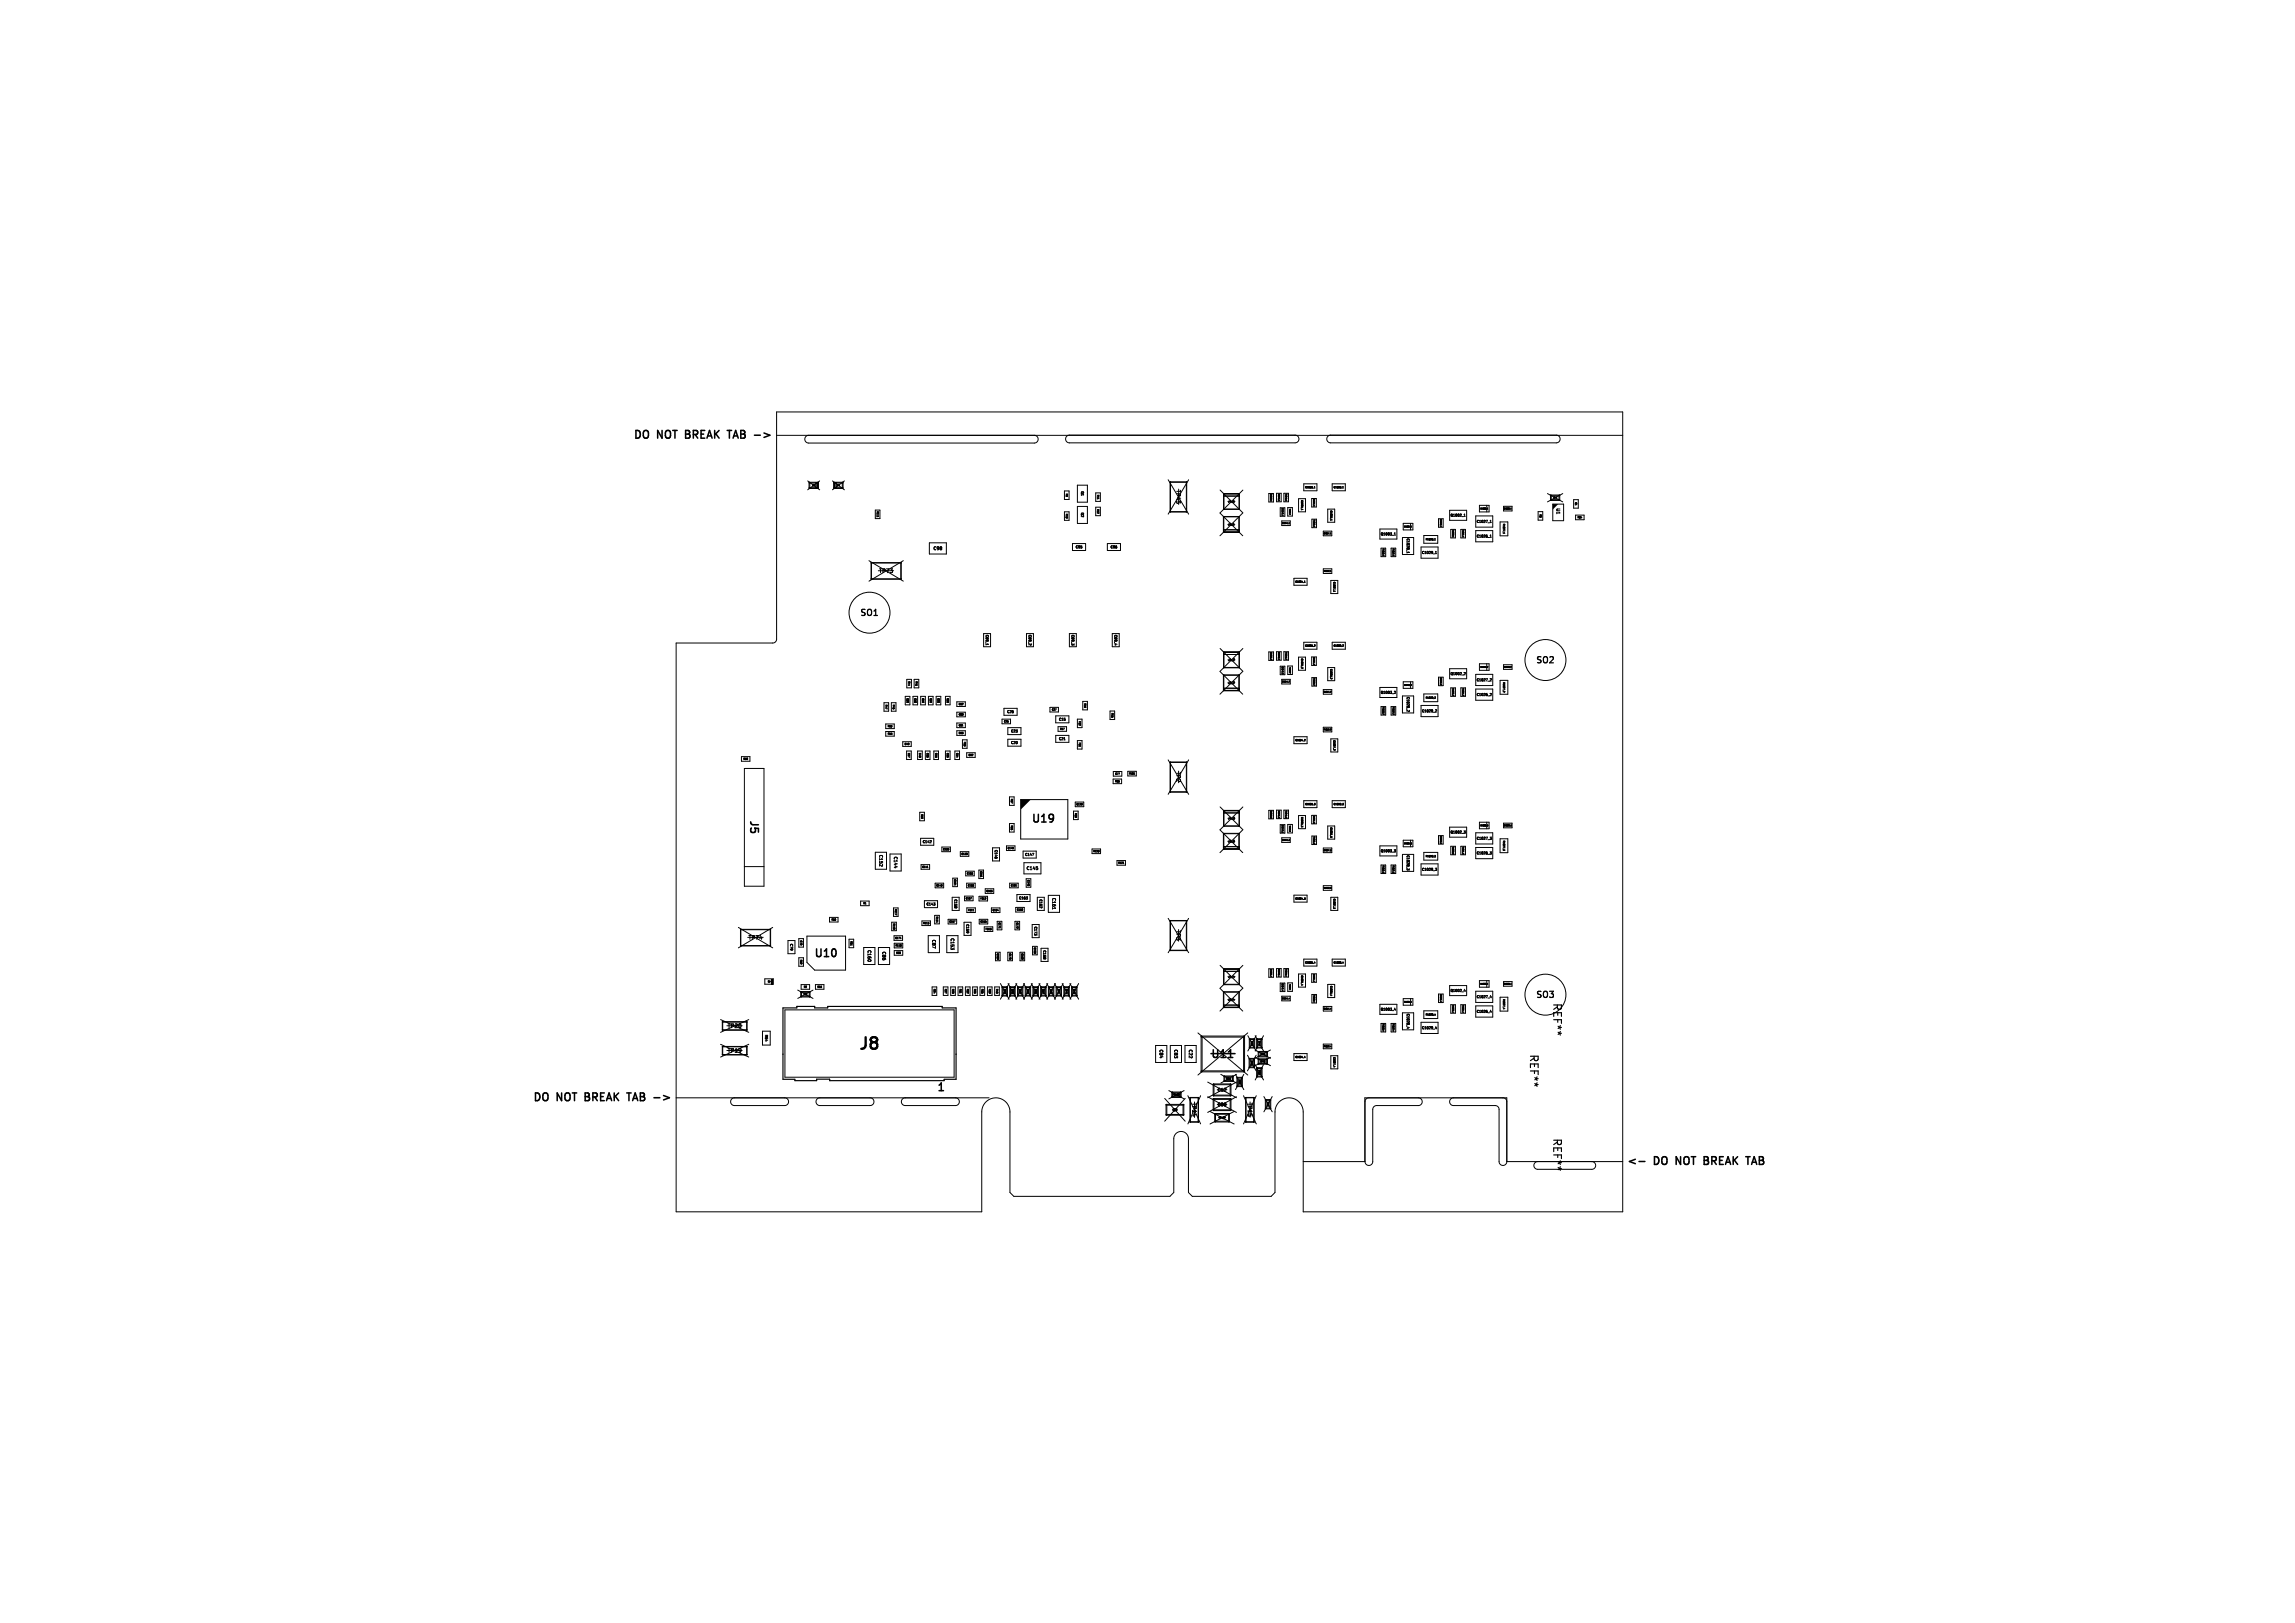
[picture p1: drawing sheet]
<svg xmlns="http://www.w3.org/2000/svg" width="297mm" height="210mm" viewBox="0 0 297 210" stroke-linecap="round" stroke-linejoin="round" font-family="sans-serif">
<defs><g id="words">
<text font-size="2.1" x="110.9" y="136.2">J8</text>
<g font-size="1.4">
<text x="81.8" y="56.8">DO</text>
<text x="85" y="56.8">NOT</text>
<text x="89" y="56.8">BREAK TAB -&gt;</text>
<text x="96.8" y="106" transform="rotate(90 96.8 106)">J5</text>
<text x="133.4" y="106.7">U19</text>
<text x="105.2" y="124.1">U10</text>
<text x="200.8" y="129.7" transform="rotate(90 200.8 129.7)">REF**</text>
<text x="156.6" y="137.2">U11</text>
<text x="197.8" y="136.3" transform="rotate(90 197.8 136.3)">REF**</text>
<text x="68.8" y="142.6">DO</text>
<text x="72" y="142.6">NOT</text>
<text x="76" y="142.6">BREAK TAB -&gt;</text>
<text x="121.2" y="141.3">1</text>
<text x="200.8" y="147.2" transform="rotate(90 200.8 147.2)">REF**</text>
<text x="210.5" y="150.8">&lt;-</text>
<text x="214.1" y="150.8">DO</text>
<text x="217.3" y="150.8">NOT</text>
<text x="221.4" y="150.8">BREAK TAB</text>
</g>
<g font-size="1.1">
<text x="111.2" y="79.9">SO1</text>
<text x="198.7" y="86">SO2</text>
<text x="198.7" y="129.3">SO3</text>
</g>
<g font-size=".7">
<text x="152.1" y="63.3" transform="rotate(90 152.1 63.3)">TP45</text>
<text x="113.7" y="74.3">TP73</text>
<text x="152.1" y="99.8" transform="rotate(90 152.1 99.8)">TP2</text>
<text x="96.8" y="121.7">TP74</text>
<text x="152.1" y="120.3" transform="rotate(90 152.1 120.3)">TP3</text>
<text x="94.1" y="133.2">TP20</text>
<text x="94.1" y="136.4">TP19</text>
<text x="154.2" y="142.6" transform="rotate(90 154.2 142.6)">TP14</text>
<text x="161.4" y="142.6" transform="rotate(90 161.4 142.6)">TP15</text>
</g>
<g font-size=".6">
<text x="201.3" y="65.7" transform="rotate(90 201.3 65.7)">U1</text>
<text x="120.7" y="71.3">C98</text>
<text x="113.7" y="110.5" transform="rotate(90 113.7 110.5)">C152</text>
<text x="115.6" y="110.8" transform="rotate(90 115.6 110.8)">C144</text>
<text x="132.8" y="112.7">C145</text>
<text x="136.1" y="116.1" transform="rotate(90 136.1 116.1)">C161</text>
<text x="112.2" y="122.9" transform="rotate(90 112.2 122.9)">C160</text>
<text x="114.1" y="123" transform="rotate(90 114.1 123)">C86</text>
<text x="120.5" y="121.5" transform="rotate(90 120.5 121.5)">C87</text>
<text x="122.9" y="121.3" transform="rotate(90 122.9 121.3)">C153</text>
<text x="150" y="135.7" transform="rotate(90 150 135.7)">C84</text>
<text x="151.9" y="135.7" transform="rotate(90 151.9 135.7)">C83</text>
<text x="153.8" y="135.7" transform="rotate(90 153.8 135.7)">C22</text>
<text x="157.5" y="143.2">C80</text>
<text x="157.5" y="141.3">C12</text>
</g>
<g font-size=".4">
<text x="139.8" y="63.5" transform="rotate(90 139.8 63.5)">Q1</text>
<text x="139.1" y="71">C95</text>
<text x="139.8" y="66.3" transform="rotate(90 139.8 66.3)">Q2</text>
<text x="143.7" y="71">C96</text>
<text x="178.6" y="69.3">Q1003_1</text>
<text x="182" y="69.6" transform="rotate(90 182 69.6)">C1028_1</text>
<text x="184" y="71.7">C1029_1</text>
<text x="187.7" y="66.9">Q1002_1</text>
<text x="191" y="67.7">C1027_1</text>
<text x="191" y="69.6">C1026_1</text>
<text x="127.5" y="82.1" transform="rotate(90 127.5 82.1)">C69_1</text>
<text x="133.1" y="82.1" transform="rotate(90 133.1 82.1)">C69_2</text>
<text x="138.6" y="82.1" transform="rotate(90 138.6 82.1)">C69_3</text>
<text x="144.2" y="82.1" transform="rotate(90 144.2 82.1)">C69_4</text>
<text x="178.6" y="89.8">Q1003_2</text>
<text x="187.7" y="87.4">Q1002_2</text>
<text x="191" y="88.2">C1027_2</text>
<text x="130.3" y="92.3">C26</text>
<text x="130.8" y="94.8">C23</text>
<text x="137" y="95.8">C21</text>
<text x="137" y="93.3">C15</text>
<text x="182" y="90.1" transform="rotate(90 182 90.1)">C1028_2</text>
<text x="184" y="92.2">C1029_2</text>
<text x="191" y="90.1">C1026_2</text>
<text x="130.8" y="96.3">C20</text>
<text x="187.7" y="107.9">Q1002_3</text>
<text x="119.4" y="109.2">C142</text>
<text x="128.7" y="109.9" transform="rotate(90 128.7 109.9)">C146</text>
<text x="132.6" y="110.8">C147</text>
<text x="178.6" y="110.3">Q1003_3</text>
<text x="182" y="110.6" transform="rotate(90 182 110.6)">C1028_3</text>
<text x="184" y="112.7">C1029_3</text>
<text x="191" y="110.6">C1026_3</text>
<text x="191" y="108.7">C1027_3</text>
<text x="119.8" y="117.2">C143</text>
<text x="123.4" y="116.3" transform="rotate(90 123.4 116.3)">C158</text>
<text x="125" y="119.5" transform="rotate(90 125 119.5)">C159</text>
<text x="131.8" y="116.4">C163</text>
<text x="133.8" y="119.8" transform="rotate(90 133.8 119.8)">C173</text>
<text x="134.5" y="116.3" transform="rotate(90 134.5 116.3)">C162</text>
<text x="102.2" y="122.1" transform="rotate(90 102.2 122.1)">C79</text>
<text x="134.9" y="122.9" transform="rotate(90 134.9 122.9)">C168</text>
<text x="178.6" y="130.8">Q1003_4</text>
<text x="182" y="131.1" transform="rotate(90 182 131.1)">C1028_4</text>
<text x="187.7" y="128.4">Q1002_4</text>
<text x="191" y="131.1">C1026_4</text>
<text x="191" y="129.2">C1027_4</text>
<text x="98.9" y="133.8" transform="rotate(90 98.9 133.8)">R54</text>
<text x="184" y="133.2">C1029_4</text>
<text x="151.7" y="143.8">Q3</text>
<text x="157.7" y="144.9">R42</text>
</g>
<g font-size=".3">
<text x="137.9" y="63.8" transform="rotate(90 137.9 63.8)">R9</text>
<text x="141.9" y="64" transform="rotate(90 141.9 64)">R11</text>
<text x="141.9" y="65.8" transform="rotate(90 141.9 65.8)">R12</text>
<text x="158.9" y="65.1">J4_1</text>
<text x="168.3" y="64.7" transform="rotate(90 168.3 64.7)">C1005_1</text>
<text x="168.9" y="63.2">C1006_1</text>
<text x="172.6" y="63.2">C1008_1</text>
<text x="201" y="64.6">R7</text>
<text x="203.8" y="65" transform="rotate(90 203.8 65)">C1</text>
<text x="113.4" y="66.1" transform="rotate(90 113.4 66.1)">R111</text>
<text x="137.9" y="66.4" transform="rotate(90 137.9 66.4)">R10</text>
<text x="158.9" y="68.1">J3_1</text>
<text x="172.1" y="66" transform="rotate(90 172.1 66)">C1003_1</text>
<text x="184.5" y="70">R1028_1</text>
<text x="194.5" y="67.7" transform="rotate(90 194.5 67.7)">R1027_1</text>
<text x="199.2" y="66.5" transform="rotate(90 199.2 66.5)">R8</text>
<text x="204.1" y="67.1">R84</text>
<text x="167.6" y="75.4">C1004_1</text>
<text x="172.5" y="75.3" transform="rotate(90 172.5 75.3)">C1007_1</text>
<text x="168.9" y="83.7">C1006_2</text>
<text x="172.6" y="83.7">C1008_2</text>
<text x="117.5" y="88.1" transform="rotate(90 117.5 88.1)">R44</text>
<text x="118.4" y="88.1" transform="rotate(90 118.4 88.1)">R45</text>
<text x="158.9" y="88.6">J3_2</text>
<text x="158.9" y="85.6">J4_2</text>
<text x="168.3" y="85.2" transform="rotate(90 168.3 85.2)">C1005_2</text>
<text x="172.1" y="86.5" transform="rotate(90 172.1 86.5)">C1003_2</text>
<text x="194.5" y="88.2" transform="rotate(90 194.5 88.2)">R1027_2</text>
<text x="114.5" y="91.1" transform="rotate(90 114.5 91.1)">R47</text>
<text x="114.8" y="95.1">R53</text>
<text x="114.8" y="94.1">R50</text>
<text x="115.5" y="91.1" transform="rotate(90 115.5 91.1)">R46</text>
<text x="117.3" y="90.3" transform="rotate(90 117.3 90.3)">C89</text>
<text x="118.3" y="90.3" transform="rotate(90 118.3 90.3)">C58</text>
<text x="119.3" y="90.3" transform="rotate(90 119.3 90.3)">C50</text>
<text x="120.3" y="90.3" transform="rotate(90 120.3 90.3)">C59</text>
<text x="121.3" y="90.3" transform="rotate(90 121.3 90.3)">C90</text>
<text x="122.5" y="90.3" transform="rotate(90 122.5 90.3)">C60</text>
<text x="124" y="95">C63</text>
<text x="124" y="92.6">C88</text>
<text x="124" y="91.3">C52</text>
<text x="124" y="94">C61</text>
<text x="124.7" y="96" transform="rotate(90 124.7 96)">FB3</text>
<text x="129.9" y="93.5">C25</text>
<text x="136.1" y="92">C27</text>
<text x="137.1" y="94.5">R17</text>
<text x="139.6" y="93.3" transform="rotate(90 139.6 93.3)">FB2</text>
<text x="140.3" y="91" transform="rotate(90 140.3 91)">R16</text>
<text x="143.8" y="92.2" transform="rotate(90 143.8 92.2)">R15</text>
<text x="167.6" y="95.9">C1004_2</text>
<text x="172.5" y="95.8" transform="rotate(90 172.5 95.8)">C1007_2</text>
<text x="184.5" y="90.5">R1028_2</text>
<text x="96.2" y="98.4">R58</text>
<text x="117" y="96.4">C49</text>
<text x="117.5" y="97.4" transform="rotate(90 117.5 97.4)">C57</text>
<text x="118.9" y="97.4" transform="rotate(90 118.9 97.4)">C48</text>
<text x="119.9" y="97.4" transform="rotate(90 119.9 97.4)">C56</text>
<text x="121" y="97.4" transform="rotate(90 121 97.4)">C53</text>
<text x="122.5" y="97.4" transform="rotate(90 122.5 97.4)">C55</text>
<text x="123.7" y="97.4" transform="rotate(90 123.7 97.4)">C54</text>
<text x="125.3" y="97.9">C92</text>
<text x="139.6" y="96.1" transform="rotate(90 139.6 96.1)">FB1</text>
<text x="144.3" y="101.3">R86</text>
<text x="144.3" y="100.3">C77</text>
<text x="146.1" y="100.3">R101</text>
<text x="119.2" y="105.3" transform="rotate(90 119.2 105.3)">R59</text>
<text x="130.8" y="103.3" transform="rotate(90 130.8 103.3)">R67</text>
<text x="130.8" y="106.8" transform="rotate(90 130.8 106.8)">R66</text>
<text x="139.1" y="105.2" transform="rotate(90 139.1 105.2)">R68</text>
<text x="139.3" y="104.2">C129</text>
<text x="158.9" y="106.1">J4_3</text>
<text x="168.3" y="105.7" transform="rotate(90 168.3 105.7)">C1005_3</text>
<text x="168.9" y="104.2">C1006_3</text>
<text x="172.1" y="107" transform="rotate(90 172.1 107)">C1003_3</text>
<text x="172.6" y="104.2">C1008_3</text>
<text x="119.3" y="112.3">C141</text>
<text x="122" y="110.1">C139</text>
<text x="123.4" y="113.8" transform="rotate(90 123.4 113.8)">C164</text>
<text x="124.4" y="110.7">C138</text>
<text x="125.1" y="113.2">C166</text>
<text x="126.8" y="112.7" transform="rotate(90 126.8 112.7)">C151</text>
<text x="130.4" y="109.9">C149</text>
<text x="132.9" y="113.8" transform="rotate(90 132.9 113.8)">C148</text>
<text x="141.5" y="110.3">R128</text>
<text x="144.7" y="111.8">R121</text>
<text x="158.9" y="109.1">J3_3</text>
<text x="184.5" y="111">R1028_3</text>
<text x="194.5" y="108.7" transform="rotate(90 194.5 108.7)">R1027_3</text>
<text x="107.6" y="119.2">R60</text>
<text x="111.7" y="117.1">R1</text>
<text x="115.5" y="119.5" transform="rotate(90 115.5 119.5)">R119</text>
<text x="115.8" y="117.6" transform="rotate(90 115.8 117.6)">R117</text>
<text x="119.4" y="119.6">R113</text>
<text x="121.1" y="118.6" transform="rotate(90 121.1 118.6)">R114</text>
<text x="121.1" y="114.7">C140</text>
<text x="122.8" y="119.4">C157</text>
<text x="125" y="116.4">C167</text>
<text x="125.2" y="114.7">C156</text>
<text x="125.3" y="117.9">FB11</text>
<text x="126.8" y="116.4">FB12</text>
<text x="126.9" y="119.4">C155</text>
<text x="127.6" y="115.5">C165</text>
<text x="128.4" y="117.9">C154</text>
<text x="129.2" y="119.3" transform="rotate(90 129.2 119.3)">C171</text>
<text x="130.8" y="114.7">C191</text>
<text x="131.5" y="119.3" transform="rotate(90 131.5 119.3)">C172</text>
<text x="131.6" y="117.9">C150</text>
<text x="167.6" y="116.4">C1004_3</text>
<text x="172.5" y="116.3" transform="rotate(90 172.5 116.3)">C1007_3</text>
<text x="103.5" y="121.7" transform="rotate(90 103.5 121.7)">C78</text>
<text x="103.5" y="124.1" transform="rotate(90 103.5 124.1)">R62</text>
<text x="110" y="121.7" transform="rotate(90 110 121.7)">R61</text>
<text x="115.8" y="121.5">C174</text>
<text x="115.9" y="122.5">R118</text>
<text x="115.9" y="123.5">R69</text>
<text x="127.5" y="120.4">FB13</text>
<text x="129" y="123.3" transform="rotate(90 129 123.3)">C189</text>
<text x="130.6" y="123.3" transform="rotate(90 130.6 123.3)">C170</text>
<text x="132.1" y="123.3" transform="rotate(90 132.1 123.3)">C169</text>
<text x="133.8" y="122.6" transform="rotate(90 133.8 122.6)">C190</text>
<text x="168.9" y="124.7">C1006_4</text>
<text x="172.6" y="124.7">C1008_4</text>
<text x="104" y="128.8">R3</text>
<text x="104" y="127.9">R2</text>
<text x="105.7" y="127.9">R63</text>
<text x="120.8" y="127.9" transform="rotate(90 120.8 127.9)">R24</text>
<text x="122.2" y="127.9" transform="rotate(90 122.2 127.9)">R27</text>
<text x="123.2" y="127.9" transform="rotate(90 123.2 127.9)">R28</text>
<text x="124.1" y="127.9" transform="rotate(90 124.1 127.9)">R31</text>
<text x="125.1" y="127.9" transform="rotate(90 125.1 127.9)">R32</text>
<text x="126" y="127.9" transform="rotate(90 126 127.9)">R35</text>
<text x="127" y="127.9" transform="rotate(90 127 127.9)">R36</text>
<text x="127.9" y="127.9" transform="rotate(90 127.9 127.9)">R39</text>
<text x="128.9" y="127.9" transform="rotate(90 128.9 127.9)">R40</text>
<text x="129.9" y="127.9" transform="rotate(90 129.9 127.9)">C28</text>
<text x="130.9" y="127.9" transform="rotate(90 130.9 127.9)">C29</text>
<text x="131.9" y="127.9" transform="rotate(90 131.9 127.9)">C32</text>
<text x="132.9" y="127.9" transform="rotate(90 132.9 127.9)">C33</text>
<text x="133.9" y="127.9" transform="rotate(90 133.9 127.9)">C36</text>
<text x="134.9" y="127.9" transform="rotate(90 134.9 127.9)">C37</text>
<text x="135.9" y="127.9" transform="rotate(90 135.9 127.9)">C40</text>
<text x="136.9" y="127.9" transform="rotate(90 136.9 127.9)">C41</text>
<text x="137.9" y="127.9" transform="rotate(90 137.9 127.9)">C44</text>
<text x="138.9" y="127.9" transform="rotate(90 138.9 127.9)">C45</text>
<text x="158.9" y="129.6">J3_4</text>
<text x="158.9" y="126.6">J4_4</text>
<text x="168.3" y="126.2" transform="rotate(90 168.3 126.2)">C1005_4</text>
<text x="172.1" y="127.5" transform="rotate(90 172.1 127.5)">C1003_4</text>
<text x="184.5" y="131.5">R1028_4</text>
<text x="194.5" y="129.2" transform="rotate(90 194.5 129.2)">R1027_4</text>
<text x="161.8" y="137.2" transform="rotate(90 161.8 137.2)">C13</text>
<text x="161.9" y="134.7" transform="rotate(90 161.9 134.7)">R88</text>
<text x="162.8" y="134.7" transform="rotate(90 162.8 134.7)">R74</text>
<text x="163.1" y="137.5">R73</text>
<text x="163.1" y="136.6">R95</text>
<text x="167.6" y="136.9">C1004_4</text>
<text x="172.5" y="136.8" transform="rotate(90 172.5 136.8)">C1007_4</text>
<text x="151.8" y="141.8">R108</text>
<text x="158.7" y="139.7">C81</text>
<text x="160.3" y="139.7" transform="rotate(90 160.3 139.7)">R87</text>
<text x="162.8" y="138.4" transform="rotate(90 162.8 138.4)">R92</text>
<text x="163.9" y="142.5" transform="rotate(90 163.9 142.5)">R41</text>
</g>
<g font-size=".2">
<text x="105.1" y="62.9">D5</text>
<text x="108.3" y="62.9">D4</text>
<text x="164.4" y="63.9" transform="rotate(90 164.4 63.9)">C1033_1</text>
<text x="165.4" y="63.9" transform="rotate(90 165.4 63.9)">R1046_1</text>
<text x="165.9" y="65.7" transform="rotate(90 165.9 65.7)">C1042_1</text>
<text x="166.3" y="63.9" transform="rotate(90 166.3 63.9)">R1045_1</text>
<text x="169.9" y="64.5" transform="rotate(90 169.9 64.5)">C1054_1</text>
<text x="191.6" y="65.9">D1000_1</text>
<text x="194.6" y="65.9">C1009_1</text>
<text x="165.9" y="67.8">C1041_1</text>
<text x="170" y="67.2" transform="rotate(90 170 67.2)">R1036_1</text>
<text x="171.3" y="69.1">C1057_1</text>
<text x="178.9" y="71" transform="rotate(90 178.9 71)">R1030_1</text>
<text x="180.2" y="71" transform="rotate(90 180.2 71)">R1032_1</text>
<text x="181.7" y="68.3">D1001_1</text>
<text x="186.3" y="67.2" transform="rotate(90 186.3 67.2)">C1010_1</text>
<text x="187.9" y="68.5" transform="rotate(90 187.9 68.5)">R1029_1</text>
<text x="189.2" y="68.5" transform="rotate(90 189.2 68.5)">R1031_1</text>
<text x="171.3" y="74">R1052_1</text>
<text x="164.4" y="84.4" transform="rotate(90 164.4 84.4)">C1033_2</text>
<text x="165.4" y="84.4" transform="rotate(90 165.4 84.4)">R1046_2</text>
<text x="165.9" y="86.2" transform="rotate(90 165.9 86.2)">C1042_2</text>
<text x="165.9" y="88.3">C1041_2</text>
<text x="166.3" y="84.4" transform="rotate(90 166.3 84.4)">R1045_2</text>
<text x="169.9" y="85" transform="rotate(90 169.9 85)">C1054_2</text>
<text x="170" y="87.7" transform="rotate(90 170 87.7)">R1036_2</text>
<text x="171.3" y="89.6">C1057_2</text>
<text x="181.7" y="88.8">D1001_2</text>
<text x="186.3" y="87.7" transform="rotate(90 186.3 87.7)">C1010_2</text>
<text x="187.9" y="89" transform="rotate(90 187.9 89)">R1029_2</text>
<text x="189.2" y="89" transform="rotate(90 189.2 89)">R1031_2</text>
<text x="191.6" y="86.4">D1000_2</text>
<text x="194.6" y="86.4">C1009_2</text>
<text x="171.3" y="94.5">R1052_2</text>
<text x="178.9" y="91.5" transform="rotate(90 178.9 91.5)">R1030_2</text>
<text x="180.2" y="91.5" transform="rotate(90 180.2 91.5)">R1032_2</text>
<text x="164.4" y="104.9" transform="rotate(90 164.4 104.9)">C1033_3</text>
<text x="165.4" y="104.9" transform="rotate(90 165.4 104.9)">R1046_3</text>
<text x="165.9" y="106.7" transform="rotate(90 165.9 106.7)">C1042_3</text>
<text x="166.3" y="104.9" transform="rotate(90 166.3 104.9)">R1045_3</text>
<text x="169.9" y="105.5" transform="rotate(90 169.9 105.5)">C1054_3</text>
<text x="191.6" y="106.9">D1000_3</text>
<text x="194.6" y="106.9">C1009_3</text>
<text x="165.9" y="108.8">C1041_3</text>
<text x="170" y="108.2" transform="rotate(90 170 108.2)">R1036_3</text>
<text x="171.3" y="110.1">C1057_3</text>
<text x="178.9" y="112" transform="rotate(90 178.9 112)">R1030_3</text>
<text x="180.2" y="112" transform="rotate(90 180.2 112)">R1032_3</text>
<text x="181.7" y="109.3">D1001_3</text>
<text x="186.3" y="108.2" transform="rotate(90 186.3 108.2)">C1010_3</text>
<text x="187.9" y="109.5" transform="rotate(90 187.9 109.5)">R1029_3</text>
<text x="189.2" y="109.5" transform="rotate(90 189.2 109.5)">R1031_3</text>
<text x="171.3" y="115">R1052_3</text>
<text x="164.4" y="125.4" transform="rotate(90 164.4 125.4)">C1033_4</text>
<text x="165.4" y="125.4" transform="rotate(90 165.4 125.4)">R1046_4</text>
<text x="166.3" y="125.4" transform="rotate(90 166.3 125.4)">R1045_4</text>
<text x="99.3" y="127.1">D3</text>
<text x="165.9" y="127.2" transform="rotate(90 165.9 127.2)">C1042_4</text>
<text x="165.9" y="129.3">C1041_4</text>
<text x="169.9" y="126" transform="rotate(90 169.9 126)">C1054_4</text>
<text x="170" y="128.7" transform="rotate(90 170 128.7)">R1036_4</text>
<text x="171.3" y="130.6">C1057_4</text>
<text x="181.7" y="129.8">D1001_4</text>
<text x="186.3" y="128.7" transform="rotate(90 186.3 128.7)">C1010_4</text>
<text x="187.9" y="130" transform="rotate(90 187.9 130)">R1029_4</text>
<text x="189.2" y="130" transform="rotate(90 189.2 130)">R1031_4</text>
<text x="191.6" y="127.4">D1000_4</text>
<text x="194.6" y="127.4">C1009_4</text>
<text x="171.3" y="135.5">R1052_4</text>
<text x="178.9" y="132.5" transform="rotate(90 178.9 132.5)">R1030_4</text>
<text x="180.2" y="132.5" transform="rotate(90 180.2 132.5)">R1032_4</text>
</g>
</g></defs>
<g fill="none" stroke="#000" stroke-width=".13">
<path d="M100.5 53.3h109.5v103.5h-41.3v-12.9a1.82 1.82 0 0 0-1.9-1.8 1.82 1.82 0 0 0-1.8 1.8v10.4l-.5 .5h-10.2l-.5-.5v-6.9a.95 .95 0 0 0-.9-1 .95 .95 0 0 0-1 1v6.9l-.5 .5h-20.2l-.5-.5v-10.4a1.82 1.82 0 0 0-1.8-1.8 1.82 1.82 0 0 0-1.8 1.8v12.9h-39.6v-73.6h12.5a.5 .5 0 0 0 .5-.5zM100.5 56.3h109.5M104.7 56.3a.5 .5 0 0 0-.5 .5 .5 .5 0 0 0 .5 .5h29.2a.5 .5 0 0 0 .5-.5 .5 .5 0 0 0-.5-.5M138 56.4l.4-.1h29.2a.5 .5 0 0 1 .5 .5 .5 .5 0 0 1-.5 .5h-29.2a.5 .5 0 0 1-.5-.3 .5 .5 0 0 1 .1-.6zM171.8 56.4l.4-.1h29.2a.5 .5 0 0 1 .5 .5 .5 .5 0 0 1-.5 .5h-29.2a.5 .5 0 0 1-.5-.3 .5 .5 0 0 1 .1-.6zM104.5 62.2l1.6 1.2M104.7 62.4l1.2 .1h-1.1zM104.7 62.4l.1 .1v.7zM104.7 63.1l1.2 .1h-1.1zM105.1 62.8h.4M105.6 62.5h.3v.7h-.3zM105.8 62.4h.1v.8z"/>
<path d="M106.1 62.2l-1.6 1.2M107.7 62.2l1.6 1.2M107.9 62.4l1.2 .1h-1.1zM107.9 63.1l1.2 .1h-1.1zM107.9 62.4l.1 .1v.7zM108 62.5h.2v.7h-.2zM108.3 62.8h.4M109 62.4l.1 .1v.7zM109.3 62.2l-1.6 1.2M112.5 72.6l4.4 2.6M112.7 72.8h3.9zM112.7 74.9h3.9z"/>
<path d="M112.7 72.8l.1 2.2zM113.3 66h.6v1.1h-.6zM113.5 66.8v.1M113.7 66.8h-.2M113.7 73.9h1.9M116.6 72.8v2.2zM116.9 72.6l-4.4 2.6M120.3 70.2h2.2v1.5h-2.2zM137.8 66.2h.6v1.1h-.6zM137.8 63.5h.6v1.1h-.6zM138.8 70.3h1.7v.9h-1.7zM139.4 65.5h1.3v2.2h-1.3z"/>
<path d="M139.4 62.8h1.3v2.2h-1.3zM141.8 63.8h.6v1.1h-.6zM141.8 65.6h.6v1.1h-.6zM142 64.5v.1M143.3 70.3h1.7v.9h-1.7zM151.2 62.1l2.6 4.4M151.4 66.2h2.2zM151.4 62.4h2.2zM151.4 62.4l.1 3.9zM152.5 63.3v2M153.5 62.4l.1 3.9zM153.8 62.1l-2.6 4.4"/>
<path d="M157.9 66.4l2.9 2.9M157.9 63.4l2.9 3M158.3 66.9v2M158.3 66.8l2.1 .1zM158.3 68.8l2.1 .1zM158.4 68.6h2v.3h-2M158.4 65.9h2zM158.4 63.9v2zM158.4 63.9h2M158.4 63.9v.3h2v-.3M158.9 67.9h.9M158.9 64.9h.9"/>
<path d="M159.6 68h.1M159.6 65h.2M160.3 66.8l.1 2.1zM160.4 63.9v2zM160.8 66.4l-2.9 2.9M160.8 63.4l-2.9 3M164.2 63.9h.6v1.1h-.6zM164.4 64.8v.1M164.5 64.8h.1M164.6 64.8h-.2M165.2 63.8h.6v1.1h-.6zM165.4 64.8h.1"/>
<path d="M165.5 64.8h.1M165.6 64.8h-.2M165.7 65.7h.6v1.1h-.6zM165.9 67.4h1.1v.6h-1.1zM165.9 66.6v.1M166 66.6h.1M166 66.6v.1M166 66.7h-.1M166.2 63.8h.6v1.1h-.6zM166.4 64.8h.1M166.5 64.8h-.1M166.7 65.7h.6v1.1h-.6z"/>
<path d="M166.8 67.8h.1M166.8 67.7v.1M166.8 67.7h.1M166.9 65.9h.1M166.9 66.1h.1M166.9 66.2h.1M166.9 66.3h.1M166.9 66.4v.2M166.9 66.6h.1M166.9 66h.1M167 66h-.1M167 65.9h.1"/>
<path d="M167 66h.1M167 66.2h-.1M167 66.2h.1M167 66.3h-.1M167 66.3h.1M167 66.1h.1M167 66.4h.1M167 66.5h.1M167 66.4h-.1M167 66.5v.1M167.5 74.8h1.7v.9h-1.7zM168.1 64.5h.9v1.7h-.9z"/>
<path d="M168.4 65.9v.1M168.6 65.9h-.2M168.7 62.6h1.7v.9h-1.7zM168.8 75.4h.1M168.8 75.2h.1v.2M169.8 64.5h.6v1.1h-.6zM169.8 67.2h.6v1.1h-.6zM170 65.4v.1M170 68.1v.1M170 68.1h.2M170.1 63.1h.1M170.1 65.4h.1"/>
<path d="M170.1 63v.1M170.1 63h.1M170.1 65.4v.1M170.1 65.5h-.1M170.1 68.1h.1M171.3 68.7h1.1v.6h-1.1zM171.3 73.6h1.1v.6h-1.1zM171.8 65.9h.9v1.7h-.9zM172.2 69.1h.1M172.2 74h.1M172.2 67.2v.1M172.2 69v.1"/>
<path d="M172.2 69h.1M172.2 73.9h.1M172.2 73.8v.1M172.2 73.8v.2M172.2 73.8h.1M172.2 75.1h.9v1.7h-.9zM172.3 67.2h.1M172.3 67.2l.1 .1M172.4 67.3h-.2M172.4 62.6h1.7v.9h-1.7zM172.6 76.5v.1M172.7 76.5h.1h-.2"/>
<path d="M173.8 63.1h.1M173.8 63h.1M173.8 62.9v.2M173.8 62.9v.1M178.6 68.5h2.2v1.3h-2.2zM178.7 70.9h.6v1.1h-.6zM179 71.9h.1M179.1 71.9h.1M179.1 71.9h-.1M180 70.9h.6v1.1h-.6zM180.3 71.9h.1M180.4 71.9h.1"/>
<path d="M180.4 69.2h.2M180.4 69l.1-.1v.3M181.5 69.6h1.4v2.2h-1.4zM181.6 67.7h1.2v.9h-1.2zM182.1 71.4v.2M182.3 71.4l.1 .1h-.3M182.5 67.7v.9M182.6 68.2h.1M182.6 68.1h.1M182.6 68.1v.1M183.9 70.8h2.2v1.4h-2.2zM184.3 69.3h1.8v1h-1.8z"/>
<path d="M185.7 69.9h.1M185.7 69.7v.2M185.8 71.6h.1M185.8 71.4v-.1v.3M186.2 67.1h.6v1.1h-.6zM186.4 68v.1M186.5 68v.1M186.5 68.1h.1M186.5 68.1h-.1M187.6 66h2.2v1.3h-2.2zM187.8 68.5h.6v1.1h-.6zM188 69.4v.1"/>
<path d="M188.1 69.4h.1M188.1 69.4l-.1 .1M189.1 68.5h.6v1.1h-.6zM189.3 69.5h.1M189.3 69.4v.1M189.4 69.4h.1M189.4 69.4v.1M189.4 69.5h.1M189.5 66.8h.1M189.5 66.6v-.1v.3M191 66.8h2.2v1.4h-2.2zM191 68.7h2.2v1.4h-2.2z"/>
<path d="M191.5 65.4h1.2v.8h-1.2zM192.4 65.4v.8M192.5 65.9h.1M192.5 65.8v.1M192.5 65.8h.1M192.8 67.6h.2M192.8 67.4l.1-.1v.3M192.8 69.3l.1-.1v.3M192.8 69.5h.2M194.1 67.5h1v1.8h-1zM194.5 68.9v.1M194.6 65.5h1.1v.6h-1.1z"/>
<path d="M194.7 68.9v.1h-.2M195.5 65.9h.1M195.5 65.8h.1M195.5 65.7v.2M195.5 65.7v.1M199.1 66.2h.6v1.1h-.6zM200.3 63.9l1.9 1M200.7 64.1h1.2l-1.2 .1zM200.7 64.7h1.2l-1.2 .1zM200.7 64.1h.1l-.1 .7zM201 65.2h1.4v2.2h-1.4zM201 64.4h.5"/>
<path d="M201.8 64.1h.1l-.1 .7zM202.2 63.9l-1.9 1M203.7 64.7h.6v1.1h-.6zM203.9 66.7h1.1v.6h-1.1zM96 97.9h1.1v.6h-1.1zM96.3 99.4h2.6v15.3h-2.6zM114.4 90.9h.6v1.1h-.6zM114.6 93.7h1.1v.6h-1.1zM114.6 94.7h1.1v.6h-1.1zM115.4 90.9h.6v1.1h-.6zM116.8 96h1.1v.6h-1.1zM117.2 90.1h.6v1.1h-.6z"/>
<path d="M117.3 97.2h.6v1.1h-.6zM117.4 87.9h.6v1.1h-.6zM118.2 90.1h.6v1.1h-.6zM118.3 87.9h.6v1.1h-.6zM118.8 97.2h.6v1.1h-.6zM119.2 90.1h.6v1.1h-.6zM119.8 97.2h.6v1.1h-.6zM120.2 90.1h.6v1.1h-.6zM120.9 97.2h.6v1.1h-.6zM121.2 90.1h.6v1.1h-.6zM122.4 90.1h.6v1.1h-.6zM122.4 97.2h.6v1.1h-.6z"/>
<path d="M123.6 97.2h.6v1.1h-.6zM123.8 92.2h1.1v.6h-1.1zM123.8 94.6h1.1v.6h-1.1zM123.8 93.6h1.1v.6h-1.1zM123.8 90.8h1.1v.6h-1.1zM124.5 93.9h.1M124.6 95.7h.6v1.1h-.6zM125.1 97.4h1.1v.6h-1.1zM127.3 82h.9v1.7h-.9zM127.6 83.3v.2M127.9 83.4h-.3M129.7 93.1h1.1v.6h-1.1z"/>
<path d="M129.9 91.7h1.7v.9h-1.7zM130.4 95.7h1.7v.9h-1.7zM130.4 94.2h1.7v.9h-1.7zM132.8 82h.9v1.7h-.9zM133.5 83.4l-.2 .1-.1-.2v.2M135.9 91.5h1.1v.6h-1.1zM136.6 92.6h1.7v.9h-1.7zM136.6 95.2h1.7v.9h-1.7zM136.9 94h1.1v.6h-1.1zM137.7 95.7h.2M138.4 82h.9v1.7h-.9zM138.7 83.4h.2"/>
<path d="M139 83.3v.2l-.1-.1M139.4 95.8h.6v1.1h-.6zM139.4 93.1h.6v1.1h-.6zM140.1 90.8h.6v1.1h-.6zM143.7 92h.6v1.1h-.6zM143.9 82h.9v1.7h-.9zM144.1 99.8h1.1v.6h-1.1zM144.4 83.3v.2M146 99.8h1.1v.6h-1.1zM151.2 98.3l2.6 4.5M151.4 98.6v3.9l.1-3.9M151.4 98.6h.1"/>
<path d="M151.4 98.6h2.2zM152.5 99.8v1.5M153.5 98.6h.1M153.5 98.6v3.9l.1-3.9M153.8 98.3l-2.6 4.5M157.9 83.9l2.9 3M158.3 87.3l2.1 .1zM158.3 87.3l.1 2.1zM158.3 89.3l2.1 .1zM158.4 89.1h2v.3h-2M158.4 86.4h2zM158.4 84.4v2z"/>
<path d="M158.4 84.4h2M158.4 84.4v.3h2v-.3M158.9 88.4h.9M158.9 85.4h.9M160.3 87.3l.1 2.1zM160.4 84.4v2zM160.8 86.9l-2.9 2.9M160.8 83.9l-2.9 3 2.9 2.9M164.2 84.4h.6v1.1h-.6zM164.4 85.4v-.1l.1 .1M164.5 85.4h.1M164.6 85.4h.1"/>
<path d="M164.6 85.3h.1M164.6 85.3v.1M165.2 84.3h.6v1.1h-.6zM165.4 85.3v-.1l.1 .1M165.5 85.3h.1M165.6 85.3h.1M165.7 86.2h.6v1.1h-.6zM165.9 87.9h1.1v.6h-1.1zM166 87.2l-.1-.1v.1M166.1 87.1v.1M166.1 87.2h-.1M166.2 84.3h.6v1.1h-.6z"/>
<path d="M166.4 85.3v-.1l.1 .1M166.5 85.3h.1M166.7 86.2h.6v1.1h-.6zM166.8 88.1h.1M166.9 88.1h.1M166.9 88.1v.1M166.9 88.2l-.1 .1h.1M166.9 88.2h.1M166.9 86.4h.1M166.9 86.7h.1M166.9 86.8h.1M166.9 86.9v.2"/>
<path d="M166.9 86.9h.1M166.9 87l.1 .1M166.9 86.5h.1M167 86.4h.1M167 86.5h.1M167 86.7h-.1M167 86.7h.1M167 86.6h.1M167 86.9h.1M167 87.1h.1M167 86.8h.1M167 87h.1"/>
<path d="M167 86.5h-.1M167 87v.1M167 86.6h-.1M167.5 95.3h1.7v.9h-1.7zM168.1 85h.9v1.7h-.9zM168.4 86.5v-.1l.2 .1M168.6 86.5h.1M168.6 86.4v.1M168.7 83.1h1.7v.9h-1.7zM168.8 95.7h.1M168.9 95.7h.1M168.9 95.7l-.1 .2h.1"/>
<path d="M169.8 85h.6v1.1h-.6zM169.8 87.7h.6v1.1h-.6zM170 88.7v-.1l.1 .1M170.1 83.5h.1M170.1 86l-.1-.1v.1M170.1 85.9v.1M170.1 86h.1M170.2 88.6h.1M170.2 88.7h-.1M170.2 88.6v.1M170.2 83.5h.1M170.2 83.5l-.1 .1h.1"/>
<path d="M171.3 89.2h1.1v.6h-1.1zM171.3 94.1h1.1v.6h-1.1zM171.8 86.4h.9v1.7h-.9zM172.2 94.3h.1M172.2 89.4v.1M172.2 89.4h.1M172.2 95.6h.9v1.7h-.9zM172.3 94.4l-.1 .1h.1M172.3 89.5h.1M172.3 94.4h.1M172.3 89.5l-.1 .1h.1M172.3 87.8l-.1-.1v.1"/>
<path d="M172.3 87.8h.1M172.4 87.8h-.1M172.4 87.7v.1M172.4 87.8h.1M172.4 83.1h1.7v.9h-1.7zM172.6 97.1v-.2l.1 .2M172.7 97.1h.1M172.8 97.1h-.1M172.8 97h.1M172.8 97v.1M173.8 83.4h.1M173.8 83.4v.1"/>
<path d="M173.8 83.5h.1M173.9 83.5h.1M173.9 83.5l-.2 .1h.2M178.6 89h2.2v1.3h-2.2zM178.7 91.4h.6v1.1h-.6zM179 92.4v-.1l.1 .1M179.1 92.4h.1M180 91.4h.6v1.1h-.6zM180.3 92.4v-.1l.1 .1M180.4 92.4h.1M180.5 89.4l.1 .1-.2 .2h.2M181.5 90.1h1.4v2.2h-1.4z"/>
<path d="M181.6 88.2h1.2v.9h-1.2zM182.4 91.9l-.1 .2-.2-.2v.2M182.5 88.2v.9M182.6 88.6h.1M182.7 88.6h.1M182.7 88.6l-.1 .1h.1M183.9 91.3h2.2v1.4h-2.2zM184.3 89.8h1.8v1h-1.8zM185.7 90.2h.1M185.8 90.2h.1M185.8 91.9h.1l-.2 .2h.2M185.8 90.2l-.1 .2h.1"/>
<path d="M186.2 87.6h.6v1.1h-.6zM186.4 88.6v-.1l.1 .1M186.5 88.6h.1M187.6 86.5h2.2v1.3h-2.2zM187.8 89h.6v1.1h-.6zM188 90v-.1l.1 .1M188.1 90h.1M188.1 89.9v.1M189.1 89h.6v1.1h-.6zM189.3 90v-.1l.1 .1M189.4 90h.1M189.4 89.9v.1"/>
<path d="M189.5 87l.1 .1-.2 .2h.2M191 87.3h2.2v1.4h-2.2zM191 89.2h2.2v1.4h-2.2zM191.5 85.9h1.2v.8h-1.2zM192.4 85.9v.8M192.5 86.2h.1M192.5 86.3l-.1 .1h.1M192.5 86.3h.1M192.8 89.7h.2M192.8 87.8h.2M193 89.7h.1M193 87.8h.1"/>
<path d="M193 87.8l-.2 .3h.2M193 89.7l-.2 .3h.2M194.1 88h1v1.8h-1zM194.6 86h1.1v.6h-1.1zM194.7 89.5l-.2-.1v.1M194.7 89.5h.1M194.7 89.4v.1M195.5 86.2h.1M195.6 86.2v.1M195.6 86.3l-.1 .1h.1M195.6 86.3h.1M96.3 112.1h2.6"/>
<path d="M107.4 118.7h1.1v.6h-1.1zM111.4 116.6h1.1v.6h-1.1zM113.3 110.3h1.4v2.2h-1.4zM114.2 112l-.2 .1-.2-.3v.3M115.2 110.5h1.4v2.2h-1.4zM115.4 119.3h.6v1.1h-.6zM115.6 117.5h.6v1.1h-.6zM115.9 112.1v.2M116 118.3v.1l-.2-.1M119 105.1h.6v1.1h-.6zM119.1 108.5h1.7v.9h-1.7zM119.2 111.9h1.1v.6h-1.1z"/>
<path d="M119.3 119.2h1.1v.6h-1.1zM119.6 116.5h1.7v.9h-1.7zM120 112.3h.1M120 112.1v.2M120.1 119.4h.1h-.1M120.2 119.4h.1M120.2 119.5v.1M120.2 119.4v.1M120.2 119.5h.1M120.5 108.8v.1l-.2 .2h.2M120.8 116.8h.2l-.1 .1M120.9 116.9l.1 .2"/>
<path d="M121 118.4h.6v1.1h-.6zM121 117.1h-.1M121 117.1h.1M121 114.3h1.1v.6h-1.1zM121.2 119.2v.2M121.9 109.6h1.1v.6h-1.1zM121.9 114.5h.1M121.9 114.5v.2M122.7 119h1.1v.6h-1.1zM122.8 109.8h.1M122.8 109.9h.1M122.8 109.8v.1"/>
<path d="M122.8 109.9v.1M123.2 116.1h.9v1.7h-.9zM123.3 113.6h.6v1.1h-.6zM123.5 119.1h.1l-.1 .2M123.6 117.4h.1M123.6 114.4v.1M123.7 117.4l.1 .1M123.8 117.5h.1M123.8 117.4v.1M124.3 110.2h1.1v.6h-1.1zM124.8 119.3h.9v1.7h-.9zM124.8 116h1.1v.6h-1.1z"/>
<path d="M125 112.7h1.1v.6h-1.1zM125.1 114.3h1.1v.6h-1.1zM125.1 117.5h1.1v.6h-1.1zM125.2 110.4h.1M125.2 110.5v.1M125.2 110.4v.1M125.6 116.1h.1l-.1 .2M125.8 112.9h.1M125.8 113h.1M125.9 113.1h-.1M125.9 113h.1M125.9 113.1h.1"/>
<path d="M125.9 113v.1M125.9 117.9h.1M125.9 114.5h.1M126 114.5v.1M126 114.7h.1M126 114.6h.1M126 114.6v.1M126.7 112.6h.6v1.1h-.6zM126.7 116h1.1v.6h-1.1zM126.7 119h1.1v.6h-1.1zM126.9 113.4v.1M127.1 113.4h-.2"/>
<path d="M127.4 119.9h1.1v.6h-1.1zM127.5 115h1.1v.6h-1.1zM127.5 119.1h.1M127.6 119.2h.1M127.6 119.2v.1M127.6 119.3h.1M128.3 115.2h.1M128.3 117.5h1.1v.6h-1.1zM128.4 115.3h.1M128.4 115.4h.1M128.4 115.3v.1M128.5 109.7h.9v1.7h-.9z"/>
<path d="M128.8 111h.2M129.1 119.2h.6v1.1h-.6zM129.1 111h.1M129.1 117.8h.1M129.3 120v.1M130.3 109.5h1.1v.6h-1.1zM130.6 103.1h.6v1.1h-.6zM130.6 106.6h.6v1.1h-.6zM130.7 114.3h1.1v.6h-1.1zM131.1 109.6v.2M131.1 109.7v.1M131.4 119.2h.6v1.1h-.6z"/>
<path d="M131.4 114.7h.2M131.5 117.4h1.1v.6h-1.1zM131.5 114.5v.2M131.6 115.8h1.7v.9h-1.7zM132.1 103.5h6.1v5.1h-6.1zM132.3 117.6h.1M132.3 117.6v.2M132.4 110.1h1.7v.9h-1.7zM132.5 111.6h2.2v1.5h-2.2zM132.8 116h.2l-.1 .2M132.8 113.7h.6v1.1h-.6zM132.9 116.2v.1"/>
<path d="M133 114.6h.1M133.1 114.6h.1M133.2 114.6h.1M133.6 119.6h.9v1.7h-.9zM133.6 110.4h.2l-.1 .3M134.1 112.1h.2M134.2 112.3l.1 .1-.1 .1M134.2 116.1h.9v1.7h-.9zM134.6 117.5v-.2l.2 .2M134.8 117.5h.1M134.9 117.4l-.1 .1M135.7 115.9h1.4v2.2h-1.4z"/>
<path d="M136.2 117.4v.2M136.6 117.5h-.4M138.9 105h.6v1.1h-.6zM139.2 103.8h1.1v.6h-1.1zM140 104h.1M140 104.1h.1M140 104.1v.1M140 104v.1M141.3 109.9h1.1v.6h-1.1zM142.2 110.1h.1M142.2 110.1v.1M142.2 110.2h.1"/>
<path d="M144.1 100.8h1.1v.6h-1.1zM144.6 111.4h1.1v.6h-1.1zM145.3 111.7h.1M145.4 111.6v.1M146.7 100.2h.1M146.8 100v.2M151.2 118.8l2.6 4.5M151.4 119.1h2.2zM151.4 119.1l.1 3.9zM151.4 102.5h2.2zM153.5 119.1l.1 3.9zM153.8 118.8l-2.6 4.5"/>
<path d="M157.9 107.4l2.9 2.9M157.9 104.4l2.9 3M158.3 107.9v2M158.3 107.8l2.1 .1zM158.4 109.8h2M158.4 109.6h2v.3M158.4 104.9h2zM158.4 106.9h2zM158.4 104.9v2zM158.4 104.9h2v.3h-2zM158.9 108.9h.9M158.9 105.9h.9"/>
<path d="M160.3 107.8l.1 2.1zM160.4 104.9v2zM160.8 107.4l-2.9 2.9M160.8 104.4l-2.9 3M164.2 104.9h.6v1.1h-.6zM164.4 105.8v.1M164.4 105.9h.1M164.5 105.9h.1M164.5 105.8h.1M164.5 105.8v.1M164.6 105.8v.1l-.1-.1M165.2 104.8h.6v1.1h-.6z"/>
<path d="M165.4 105.8h.1M165.5 105.8h.1M165.6 105.7v.1h-.1M165.7 106.7h.6v1.1h-.6zM165.9 108.4h1.1v.6h-1.1zM165.9 107.6v.1M165.9 107.7h.1M166 107.7h.1M166.1 107.6v.1h-.1M166.2 104.8h.6v1.1h-.6zM166.4 105.8h.1M166.5 105.8h.1"/>
<path d="M166.5 105.7v.1M166.7 106.7h.6v1.1h-.6zM166.8 108.6h.1l-.1 .1M166.8 108.7h.1M166.9 108.7h.1M166.9 108.8h-.1M166.9 108.8h.1M166.9 108.7v.1M166.9 106.9h.1M166.9 107.1h.1M166.9 107.2h.1M166.9 107.3h.1"/>
<path d="M166.9 107.4v.2M166.9 107.4h.1M166.9 107.5h.1M166.9 107h.1M166.9 107.6h.1M167 107h-.1M167 106.9h.1M167 107h.1M167 107.6h-.1M167 107.6h.1M167 107.2h-.1M167 107.2h.1"/>
<path d="M167 107.3h-.1M167 107.3h.1M167 107.1h.1M167 107.4h.1M167 107.5v.1M167.5 115.8h1.7v.9h-1.7zM168.1 105.5h.9v1.7h-.9zM168.4 106.9l.1 .1M168.5 107h.1M168.6 106.9v.1h-.1M168.7 103.6h1.7v.9h-1.7zM168.8 116.2h.1"/>
<path d="M168.8 116.4h.1M168.9 116.2v.1M168.9 116.3h.1M168.9 116.4h.1M168.9 116.3v.1M169.8 105.5h.6v1.1h-.6zM169.8 108.2h.6v1.1h-.6zM170 106.4v.1M170 106.5h.1M170 109.1v.1M170 109.2h.1M170.1 106.5h-.1"/>
<path d="M170.1 103.9h.1v.1M170.1 106.5h.1M170.1 109.2h.1M170.1 106.4v.1M170.2 109.1l-.1 .1M170.2 104.1h-.1M170.2 104v.1M170.2 104.1h.1M171.3 109.7h1.1v.6h-1.1zM171.3 114.6h1.1v.6h-1.1zM171.8 106.9h.9v1.7h-.9zM172.2 109.9v.1"/>
<path d="M172.2 114.8v.1M172.2 108.3h.1M172.2 108.2v.1M172.2 110.1h.1M172.2 116.1h.9v1.7h-.9zM172.2 114.9h.1M172.2 110h.1M172.2 115h.1M172.3 114.9h.1M172.3 110h.1M172.3 110.1h-.1M172.3 110v.1"/>
<path d="M172.3 114.9v.1M172.3 108.3h.1M172.4 108.2v.1h-.1M172.4 103.6h1.7v.9h-1.7zM172.6 117.5h.1M172.7 117.5h.1M172.8 117.4v.2l-.1-.1M173.7 103.9h.2l-.1 .1M173.8 104.1h.1M173.8 104h.1M173.9 104v.1M173.9 104.1h-.1"/>
<path d="M173.9 104.1h.1M178.6 109.5h2.2v1.3h-2.2zM178.7 111.9h.6v1.1h-.6zM179 112.9h.1M179.1 112.9h-.1M179.1 112.8v.1M180 111.9h.6v1.1h-.6zM180.3 112.9h.1M180.4 112.9h-.1M180.4 112.8v.1M180.4 109.9h.2l-.1 .2M180.5 110.2h.1"/>
<path d="M180.5 110.1h.1M180.6 110.1h.1M180.6 110.2h-.1M180.6 110.2h.1M180.6 110.1v.1M181.5 110.6h1.4v2.2h-1.4zM181.6 108.7h1.2v.9h-1.2zM182.1 112.4v.2h.1M182.3 112.5l-.1 .1M182.4 112.4v.2l-.1-.1M182.5 108.7v.9M182.6 109.1h.1"/>
<path d="M182.7 109.1h.1M182.7 109.2h-.1M182.7 109.1v.1M182.7 109.2h.1M183.9 111.8h2.2v1.4h-2.2zM184.3 110.3h1.8v1h-1.8zM185.7 110.7h.1v.1M185.7 112.3h.2l-.1 .2 .1 .1M185.8 110.8h.1M185.8 110.9h-.1M185.8 110.8v.1M185.8 110.9h.1"/>
<path d="M185.9 112.6h-.1M185.9 112.6h.1M186.2 108.1h.6v1.1h-.6zM186.4 109.1h.1M186.5 109.1h-.1M186.5 109.1h.1M186.5 109v.1M187.6 107h2.2v1.3h-2.2zM187.8 109.5h.6v1.1h-.6zM188 110.4v.1M188 110.5h.1M188.1 110.5h-.1"/>
<path d="M188.1 110.5h.1M188.1 110.4v.1M189.1 109.5h.6v1.1h-.6zM189.3 110.5h.1M189.3 110.4v.1M189.4 110.5h-.1M189.4 110.5h.1M189.4 110.4v.1M189.4 107.5h.2l-.1 .1 .1 .1M189.6 107.7h.1M189.6 107.7v.1h-.1M191 107.8h2.2v1.4h-2.2z"/>
<path d="M191 109.7h2.2v1.4h-2.2zM191.5 106.4h1.2v.8h-1.2zM192.4 106.4v.8M192.4 106.7h.1v.1M192.5 106.8h.1M192.5 106.9h.1M192.5 106.8v.1M192.8 110.2h.2l-.1 .1h.1M192.8 108.3h.2l-.1 .1h.1M193 110.3v.1M193 108.4v.1M193 108.5v.1"/>
<path d="M193 110.4v.1h-.1M193 108.6h-.1M193 108.6h.1M194.1 108.5h1v1.8h-1zM194.5 110h.1M194.6 110h.1M194.6 106.5h1.1v.6h-1.1zM194.7 109.9v.1h-.1M195.5 106.7l.1 .1M195.6 106.8h.1M195.6 106.9h-.1M195.6 106.8v.1"/>
<path d="M195.6 106.9h.1M93.3 131.9l3.6 1.7M93.3 135.1l3.6 1.7M93.5 135.4h3.2zM93.5 136.5h3.2zM93.5 135.4v1.1zM93.5 132.2h3.2zM93.5 133.3h3.2zM93.5 132.2v1.1zM94.1 132.7h1.9M94.1 135.9h1.9M95.6 120l4.4 2.7"/>
<path d="M95.9 120.3h3.8M95.9 122.4h3.8M95.9 120.3v2.1M96.6 132.2l.1 1.1zM96.6 135.4l.1 1.1zM96.8 121.3h2M96.9 131.9l-3.6 1.7M96.9 135.1l-3.6 1.7M98.7 133.4h1v1.8h-1zM99 126.7h1.1v.7h-1.1zM99.7 120.3v2.1M100 120l-4.4 2.7"/>
<path d="M101.6 130.7h21.9v8.7h-21.9zM102 121.7h.9v1.7h-.9zM103.2 128.1l2 1.1M103.4 121.5h.6v1.1h-.6zM103.4 123.9h.6v1.1h-.6zM103.6 128.3l1.2 .1h-1.1zM103.6 128.3h.1v.7zM103.6 128.9l1.2 .1h-1.1zM103.7 127.4h1.1v.6h-1.1zM104 128.6h.4M104.4 121.1h5v4.4h-4l-1-1zM104.7 128.3l.1 .1v.6z"/>
<path d="M105.2 128.1l-2 1.1M105.5 127.4h1.1v.6h-1.1zM109.9 121.5h.6v1.1h-.6zM110.1 122.2v.1M111.8 122.6h1.4v2.2h-1.4zM112.4 124.4h.3M113.7 122.6h1.4v2.2h-1.4zM115.6 120.2h.1M115.7 120.2h.1M115.7 121.1h1.1v.6h-1.1zM115.7 122.1h1.1v.6h-1.1zM115.7 123h1.1v.6h-1.1z"/>
<path d="M115.8 120.2h-.1M116.5 121.4h.1M116.6 122.3h.1M116.6 122.4h.1M116.6 122.3v.1M120.1 121.1h1.5v2.2h-1.5zM120.6 127.7h.6v1.1h-.6zM122.1 127.7h.6v1.1h-.6zM122.5 121.1h1.5v2.2h-1.5zM123 127.7h.6v1.1h-.6zM123.1 122.8v.1l.2-.1M123.5 122.6v.3l-.2-.2"/>
<path d="M124 127.7h.6v1.1h-.6zM124.2 128.4v.1M124.9 127.7h.6v1.1h-.6zM125.2 120.6v.1M125.2 120.7h.1M125.4 120.6l-.3 .1M125.9 127.7h.6v1.1h-.6zM126.8 127.7h.6v1.1h-.6zM127.8 127.7h.6v1.1h-.6zM128.7 127.7h.6v1.1h-.6zM128.8 123.2h.6v1.1h-.6zM129.1 124.1h.1"/>
<path d="M129.2 124.1h-.1M129.2 124.1h.1M129.4 120l-.1 .1M129.5 127.3l1.1 2M129.7 127.7h.7l-.7 .1zM129.7 127.7h.1l-.1 1.2zM129.7 128.8h.7l-.7 .1zM130 128v.6M130.3 127.7h.1l-.1 1.2zM130.4 123.2h.6v1.1h-.6zM130.5 127.3l1.1 2M130.6 127.3l-1.1 2"/>
<path d="M130.7 124.1h.1M130.7 127.7h.7l-.7 .1zM130.7 127.7h.1l-.1 1.2zM130.7 128.8h.7l-.7 .1zM130.8 124.1h.1M131 128v.6M131.3 127.7h.1l-.1 1.2zM131.5 127.3l1.1 2M131.6 120.1v-.1l.1 .1M131.6 127.3l-1.1 2M131.7 127.7h.7l-.7 .1zM131.7 127.7h.1l-.1 1.2z"/>
<path d="M131.7 128.8h.7l-.7 .1zM131.7 120.1h.1M131.8 120.1h-.1M131.8 120.1h.1M132 123.2h.6v1.1h-.6zM132 128v.6M132.2 124.1h.1M132.3 124.1h.1M132.3 127.7h.1l-.1 1.2zM132.4 124.1h-.1M132.4 124.1h.1M132.5 127.3l1.1 2"/>
<path d="M132.6 127.3l-1.1 2M132.7 127.7h.7l-.7 .1zM132.7 127.7h.1l-.1 1.2zM132.7 128.8h.7l-.7 .1zM133 128v.6M133.3 127.7h.1l-.1 1.2zM133.5 127.3l1.1 2M133.6 127.3l-1.1 2M133.6 122.5h.6v1.1h-.6zM133.7 127.7h.7l-.7 .1zM133.7 127.7h.1l-.1 1.2zM133.7 128.8h.7l-.7 .1z"/>
<path d="M133.9 123.3h.1M133.9 120.9h.2M134 123.3h.1M134 128v.6M134.2 120.8v.2l-.1-.1M134.3 127.7h.1l-.1 1.2zM134.5 127.3l1.1 2M134.6 127.3l-1.1 2M134.7 127.7h.7l-.7 .1zM134.7 127.7h.1l-.1 1.2zM134.7 128.8h.7l-.7 .1zM134.7 122.7h.9v1.7h-.9z"/>
<path d="M135 128v.6M135.1 124h.1M135.2 124l.1 .1M135.3 124.1h.1M135.3 127.7h.1l-.1 1.2zM135.3 124v.1M135.5 127.3l1.1 2M135.6 127.3l-1.1 2M135.7 127.7h.7l-.7 .1zM135.7 127.7h.1l-.1 1.2zM135.7 128.8h.7l-.7 .1zM136 128v.6"/>
<path d="M136.3 127.7h.1l-.1 1.2zM136.5 127.3l1.1 2M136.6 127.3l-1.1 2M136.7 127.7h.7l-.7 .1zM136.7 127.7h.1l-.1 1.2zM136.7 128.8h.7l-.7 .1zM136.9 128.4v.1M137 128v.6M137.3 127.7h.1l-.1 1.2zM137.5 127.3l1.1 2M137.6 127.3l-1.1 2M137.7 127.7h.7l-.7 .1z"/>
<path d="M137.7 127.7h.1l-.1 1.2zM137.7 128.8h.7l-.7 .1zM138 128v.6M138.3 127.7h.1l-.1 1.2zM138.5 127.3l1.1 2M138.6 127.3l-1.1 2M138.7 127.7h.7l-.7 .1zM138.7 127.7h.1l-.1 1.2zM138.7 128.8h.7l-.7 .1zM139 128v.6M139.3 127.7h.1l-.1 1.2zM139.6 127.3l-1.1 2"/>
<path d="M149.6 135.3h1.4v2.2h-1.4zM151.4 123h2.2zM151.5 135.3h1.4v2.2h-1.4zM152.5 120.3v1.5M153.4 135.3h1.4v2.2h-1.4zM155 133.7l6.5 5.4M155.5 138.6h5.6l-5.6 .1zM155.5 134.1h5.6l-5.6 .1zM155.5 134.1h.1l-.1 4.6zM157.9 127.9l2.9 2.9M157.9 124.9l2.9 3M158 139l2 1.1"/>
<path d="M158.3 128.3l2.1 .1zM158.3 128.3l.1 2.1zM158.3 130.3l2.1 .1zM158.4 130.1h2v.3h-2M158.4 127.4h2zM158.4 125.4v2zM158.4 125.4h2M158.4 125.4v.3h2v-.3M158.4 139.2l1.2 .1h-1.1zM158.4 139.8l1.2 .1h-1.1zM158.4 139.2l.1 .1v.6zM158.7 139.6h.6"/>
<path d="M158.9 129.3h.9M158.9 126.4h.9M159.1 139.7h.2M159.5 139.2l.1 .1v.6zM159.9 139l1.1 2M160 139l-2 1.1M160.1 139.4l.7 .1h-.7zM160.1 139.4l.1 .1-.1 1.1zM160.3 128.3l.1 2.1zM160.4 125.4v2zM160.4 139.7v.6M160.7 139.4l.1 .1-.1 1.1z"/>
<path d="M160.8 127.9l-2.9 2.9M160.8 124.9l-2.9 3M161 134.1h.1l-.1 4.6zM161 139l-1.1 2M161.4 136.5l1.2 2.1M161.5 133.7l-6.5 5.4M161.5 134l1.1 2M161.7 137h.7l-.7 .1zM161.7 137h.1l-.1 1.2zM161.7 138.1h.7l-.7 .1zM161.7 134.4l.7 .1h-.7zM161.7 135.5l.7 .1h-.7z"/>
<path d="M161.7 134.4l.1 .1-.1 1.1zM162 137.2v.7M162 134.7v.6M162.3 137h.1l-.1 1.2zM162.3 134.4l.1 .1-.1 1.1zM162.4 137.8l1.1 1.9M162.4 134l1.1 2M162.4 136.8l2 1.1M162.4 135.9l2 1M162.6 134l-1.1 2M162.6 136.5l-1.2 2.1M162.6 138.2h.7l-.6 .1z"/>
<path d="M162.6 138.2h.1v1.2zM162.6 139.3h.7l-.6 .1zM162.6 134.4l.7 .1h-.6zM162.6 135.5l.7 .1h-.6zM162.6 134.4l.1 .1v1.1zM162.8 137l1.2 .1h-1.1zM162.8 137h.1v.7zM162.8 137.6l1.2 .1h-1.1zM162.8 136.1h1.2l-1.1 .1zM162.8 136.1h.1v.7zM162.8 136.7h1.2l-1.1 .1zM163 138.5v.6"/>
<path d="M163 134.7v.6M163.1 137.3h.6M163.1 136.4h.6M163.2 138.2h.1v1.2zM163.2 134.4l.1 .1v1.1zM163.5 137.8l-1.1 1.9M163.5 134l-1.1 2M163.9 136.1h.1v.7zM163.9 137l.1 .1v.6zM164.2 125.4h.6v1.1h-.6zM164.4 136.8l-2 1.1M164.4 135.9l-2 1"/>
<path d="M164.4 126.4h.1M164.6 126.3h-.1v.1M165.2 125.3h.6v1.1h-.6zM165.4 126.3h.1M165.6 126.3h-.1M165.7 127.2h.6v1.1h-.6zM165.9 128.9h1.1v.6h-1.1zM165.9 128.2h.1M166.1 128.2l-.1-.1v.1M166.2 125.3h.6v1.1h-.6zM166.4 126.3h.1M166.5 126.3h-.1"/>
<path d="M166.7 127.2h.6v1.1h-.6zM166.8 129.1v.1h.1M166.9 129.2v.1M166.9 127.4h.1M166.9 127.6h.1M166.9 127.7h.1M166.9 127.8h.1M166.9 127.9v.1M166.9 127.5h.1M166.9 128.1h.1M167 127.5h-.1M167 127.4h.1"/>
<path d="M167 127.5h.1M167 127.7h-.1M167 127.7h.1M167 127.8h-.1M167 127.8h.1M167 127.6h.1M167 127.9h.1M167 127.6h-.1M167 127.9h-.1M167 128l-.1 .1M167.5 136.3h1.7v.9h-1.7zM168.1 126h.9v1.7h-.9z"/>
<path d="M168.4 127.5h.1M168.6 127.4h-.1v.1M168.7 124.1h1.7v.9h-1.7zM168.8 136.7v.1h.1M168.9 136.7v.2M169.8 126h.6v1.1h-.6zM169.8 128.7h.6v1.1h-.6zM170 127h.1M170 129.7h.1M170.1 124.4v.2h.1M170.1 127l-.1-.1v.1M170.2 129.6h-.1v.1"/>
<path d="M170.2 124.5v.1M171.3 130.2h1.1v.6h-1.1zM171.3 135.1h1.1v.6h-1.1zM171.8 127.4h.9v1.7h-.9zM172.2 128.8h.1M172.2 130.4v.1h.1M172.2 135.3v.1h.1M172.2 136.6h.9v1.7h-.9zM172.2 130.5v.1M172.2 135.4v.1M172.4 128.8l-.1-.1v.2M172.4 124.1h1.7v.9h-1.7z"/>
<path d="M172.6 138h.1M172.8 138h-.1v.1M173.8 124.4v.2h.1M173.8 124.5v.1M178.6 130h2.2v1.3h-2.2zM178.7 132.4h.6v1.1h-.6zM179 133.4h.1M179.1 133.4h-.1M180 132.4h.6v1.1h-.6zM180.3 133.4h.1M180.4 133.4h-.1M180.5 130.4l-.1 .2h.2"/>
<path d="M180.6 130.5v.2M181.5 131.1h1.4v2.2h-1.4zM181.6 129.2h1.2v.9h-1.2zM182.1 133h.2M182.4 133l-.2-.1v.2M182.5 129.2v.9M182.6 129.6v.1h.1M182.7 129.6v.1M183.9 132.3h2.2v1.4h-2.2zM184.3 130.8h1.8v1h-1.8zM185.7 131.2v.1h.1M185.8 131.3v.1"/>
<path d="M185.8 132.8v.2h.1M185.9 132.9v.2M186.2 128.6h.6v1.1h-.6zM186.4 129.6h.1M186.6 129.6l-.2-.1v.1M187.6 127.5h2.2v1.3h-2.2zM187.8 130h.6v1.1h-.6zM188 131h.1M188.1 131l-.1-.1v.1M189.1 130h.6v1.1h-.6zM189.3 131h.1M189.4 131l-.1-.1v.1"/>
<path d="M189.5 128v.2h.1M189.6 128.1v.2M191 130.2h2.2v1.4h-2.2zM191 128.3h2.2v1.4h-2.2zM191.5 126.9h1.2v.8h-1.2zM192.4 126.9v.8M192.5 127.2v.1M192.5 127.3v.1M192.9 130.7l-.1 .2h.2M192.9 128.8l-.1 .2h.2M193 128.9v.2M193 130.8v.2"/>
<path d="M194.1 129h1v1.8h-1zM194.5 130.5h.2M194.6 127h1.1v.6h-1.1zM194.8 130.5l-.2-.1v.2M195.5 127.2v.1h.1M195.6 127.3v.1M87.5 142.1h40.5M95.1 142.1a.5 .5 0 0 0-.5 .5 .5 .5 0 0 0 .5 .5h6.5a.5 .5 0 0 0 .5-.5 .5 .5 0 0 0-.5-.5M106.1 142.1a.5 .5 0 0 0-.5 .5 .5 .5 0 0 0 .5 .5h6.5a.5 .5 0 0 0 .5-.5 .5 .5 0 0 0-.5-.5M117.2 142.1a.5 .5 0 0 0-.5 .5 .5 .5 0 0 0 .5 .5h6.5a.5 .5 0 0 0 .5-.5 .5 .5 0 0 0-.5-.5M150.7 142.1l2.7 3M150.9 142.9l2.3 .1h-2.3z"/>
<path d="M150.9 144.2l2.3 .1h-2.3zM150.9 142.9l.1 .1v1.3zM151.3 141.1l1.9 1.1M151.7 141.3l1.2 .1h-1.2zM151.7 141.3h.1l-.1 .7zM151.7 141.9l1.2 .1h-1.2zM151.7 143.6h.7M151.9 141.6h.8M152.6 141.6h.1M152.6 141.6v.1M152.6 141.7h.1M152.8 141.3l.1 .1-.1 .6z"/>
<path d="M153.1 142.9l.1 .1v1.3zM153.2 141.1l-1.9 1.1M153.4 142.1l-2.7 3M153.7 141.8l1.7 3.6M154 142h1.1zM154 145.2h1.1zM154 142v3.2zM154.6 142.6v2M155.1 142v3.2zM155.4 141.8l-1.7 3.6M156.3 141.9l3.7 2M156.3 140l3.7 2"/>
<path d="M156.6 143.8l3.1 1.6M157 142.2h2.3l-2.2 .1zM157 143.6l2.3 .1h-2.2zM157 142.2h.1v1.5zM157 140.3h2.3l-2.2 .1zM157 141.7l2.3 .1h-2.2zM157 140.3h.1v1.5zM157.2 144.1h1.9l-1.9 .1zM157.2 145.1h1.9l-1.9 .1zM157.2 144.1h.1v1.1zM157.5 142.9h1.3M157.5 141h1.3"/>
<path d="M157.7 144.6h.9M159 144.1h.1v1.1zM159.2 142.2h.1v1.5zM159.2 140.3h.1v1.5zM159.7 143.8l-3.1 1.6M160 141.9l-3.7 2M160 140l-3.7 2M160.1 140.5l.7 .1h-.7zM160.9 141.8l1.7 3.6M161.2 142h1.1zM161.2 142v3.2zM161.2 145.2h1.1z"/>
<path d="M161.8 142.6v2M162.3 142v3.2zM162.6 141.8l-1.7 3.6M163.6 141.9l1 2M163.8 142.3h.7l-.7 .1zM163.8 142.3h.1l-.1 1.2zM163.8 143.4h.7l-.7 .1zM164 143v.1M164.1 142.6v.6M164.4 142.3h.1l-.1 1.2zM164.6 141.9l-1 2M168.7 150.3h7.9v-8.2h18.4v8.2"/>
<path d="M177.2 142.1a.5 .5 0 0 0-.5 .5v7.7a.5 .5 0 0 0 .5 .5 .5 .5 0 0 0 .5-.5v-6.7a.5 .5 0 0 1 .5-.5h5.3a.5 .5 0 0 0 .6-.5 .5 .5 0 0 0-.5-.5M188.1 142.1a.5 .5 0 0 0-.5 .5 .5 .5 0 0 0 .5 .5h5.4a.5 .5 0 0 1 .5 .5v6.7a.5 .5 0 0 0 .5 .5 .5 .5 0 0 0 .5-.5M194.5 142.1a.5 .5 0 0 1 .5 .5M195 150.3h15M199 150.3a.5 .5 0 0 0-.5 .5 .5 .5 0 0 0 .5 .5h7a.5 .5 0 0 0 .5-.5 .5 .5 0 0 0-.5-.5"/>
<circle cx="112.5" cy="79.3" r="2.65"/>
<circle cx="200" cy="85.4" r="2.65"/>
<circle cx="200" cy="128.7" r="2.65"/>
</g>
<path d="M156.7 136.3h3.1M159 136.8h.5M212.1 150.3h.8M216.9 150.7v-1l.6 1M220.5 149.7h.4l.1 .1M220.5 150.1h.4M220.9 150.1l.1 .1M221 150.6l-.5 .1M221 150.1h-.1" fill="none" stroke="#000" stroke-width=".2"/>
<path d="M201 65.2h.7l-.7 .7zM132.1 103.5h1.3l-1.3 1.3zM99.8 126.7h.3v.7h-.3z" fill="#000"/>
<path d="M101.3 130.4h1.8v-.2h2.3v.2h1.7v-.2h14.8v.2h1.8v9.3h-1.5v.1h-14.8v-.2h-1.7v.2h-2.8v-.1h-1.6zM101.3 136.4h.1M123.7 136.4h.1" fill="none" stroke="#000" stroke-width=".15"/>
<use href="#words"/>
</svg>
